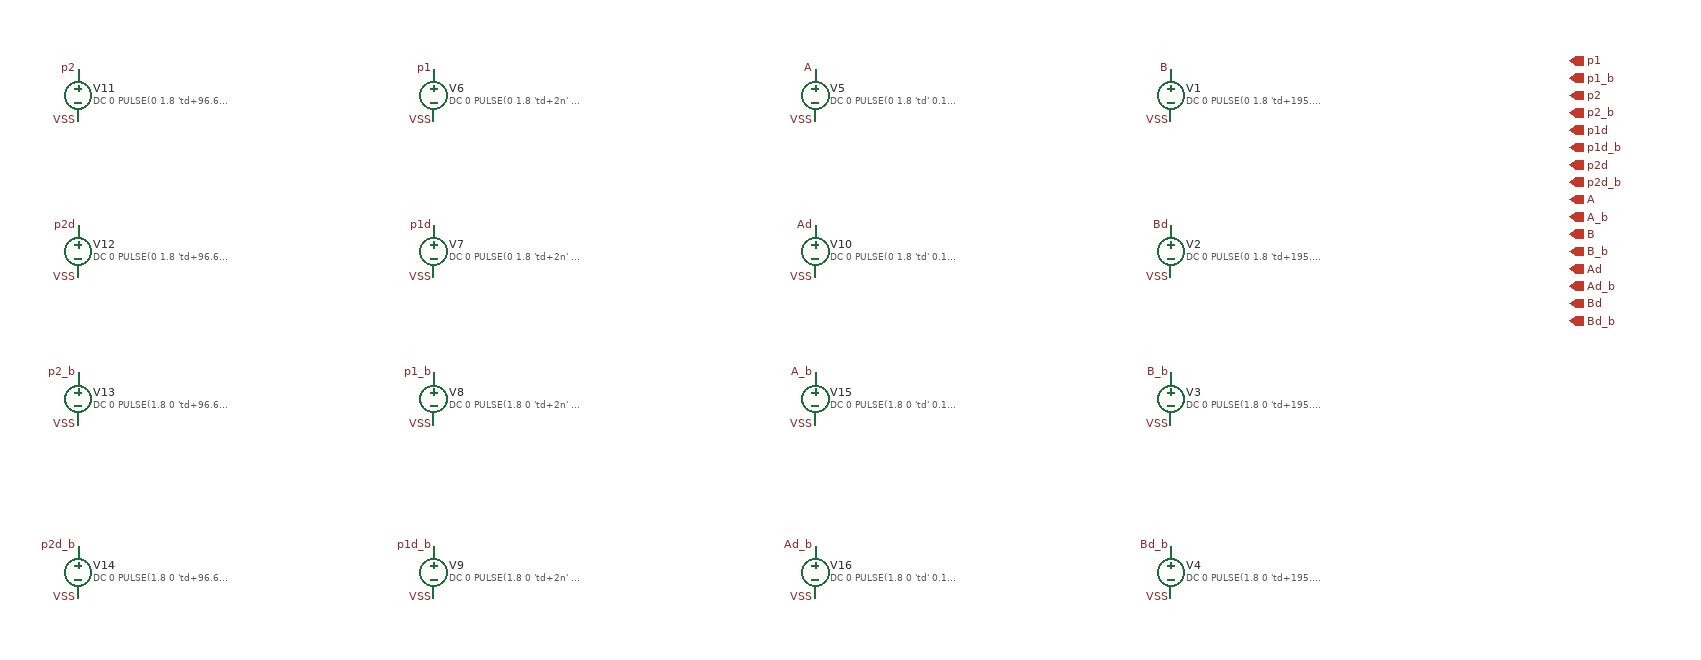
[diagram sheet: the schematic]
v {xschem version=3.0.0 file_version=1.2 }
G {}
K {}
V {}
S {}
E {}
C {devices/vsource.sym} 470 -650 0 0 {name=V6 value="DC 0 PULSE(0 1.8 'td+2n' 0.1n 0.1n 90.45625n 195.3125n)"}
C {devices/lab_pin.sym} 470 -680 3 1 {name=l25 sig_type=std_logic lab=p1}
C {devices/vsource.sym} 470 -470 0 0 {name=V7 value="DC 0 PULSE(0 1.8 'td+2n' 0.1n 0.1n 91.45625n 195.3125n)"}
C {devices/lab_pin.sym} 470 -500 3 1 {name=l27 sig_type=std_logic lab=p1d}
C {devices/vsource.sym} 470 -300 0 0 {name=V8 value="DC 0 PULSE(1.8 0 'td+2n' 0.1n 0.1n 90.45625n 195.3125n)"}
C {devices/lab_pin.sym} 470 -330 3 1 {name=l31 sig_type=std_logic lab=p1_b}
C {devices/vsource.sym} 470 -100 0 0 {name=V9 value="DC 0 PULSE(1.8 0 'td+2n' 0.1n 0.1n 91.45625n 195.3125n)"}
C {devices/lab_pin.sym} 470 -130 3 1 {name=l33 sig_type=std_logic lab=p1d_b}
C {devices/vsource.sym} 60 -650 0 0 {name=V11 value="DC 0 PULSE(0 1.8 'td+96.65625n' 0.1n 0.1n 90.45625n 195.3125n)"}
C {devices/lab_pin.sym} 60 -680 3 1 {name=l43 sig_type=std_logic lab=p2}
C {devices/vsource.sym} 60 -470 0 0 {name=V12 value="DC 0 PULSE(0 1.8 'td+96.65625n' 0.1n 0.1n 91.45625n 195.3125n)"}
C {devices/lab_pin.sym} 60 -500 3 1 {name=l45 sig_type=std_logic lab=p2d}
C {devices/vsource.sym} 60 -300 0 0 {name=V13 value="DC 0 PULSE(1.8 0 'td+96.65625n' 0.1n 0.1n 90.45625n 195.3125n)"}
C {devices/lab_pin.sym} 60 -330 3 1 {name=l47 sig_type=std_logic lab=p2_b}
C {devices/vsource.sym} 60 -100 0 0 {name=V14 value="DC 0 PULSE(1.8 0 'td+96.65625n' 0.1n 0.1n 91.45625n 195.3125n)"}
C {devices/lab_pin.sym} 60 -130 3 1 {name=l49 sig_type=std_logic lab=p2d_b}
C {devices/vsource.sym} 1320 -650 0 0 {name=V1 value="DC 0 PULSE(0 1.8 'td+195.3125n' 0.1n 0.1n 191.1125n 390.625n)"}
C {devices/lab_pin.sym} 1320 -680 3 1 {name=l2 sig_type=std_logic lab=B}
C {devices/vsource.sym} 1320 -470 0 0 {name=V2 value="DC 0 PULSE(0 1.8 'td+195.3125n' 0.1n 0.1n 193.1125n 390.625n)"}
C {devices/lab_pin.sym} 1320 -500 3 1 {name=l4 sig_type=std_logic lab=Bd}
C {devices/vsource.sym} 1320 -300 0 0 {name=V3 value="DC 0 PULSE(1.8 0 'td+195.3125n' 0.1n 0.1n 191.1125n 390.625n)"}
C {devices/lab_pin.sym} 1320 -330 3 1 {name=l6 sig_type=std_logic lab=B_b}
C {devices/vsource.sym} 1320 -100 0 0 {name=V4 value="DC 0 PULSE(1.8 0 'td+195.3125n' 0.1n 0.1n 193.1125n 390.625n)"}
C {devices/lab_pin.sym} 1320 -130 3 1 {name=l8 sig_type=std_logic lab=Bd_b}
C {devices/vsource.sym} 910 -650 0 0 {name=V5 value="DC 0 PULSE(0 1.8 'td' 0.1n 0.1n 191.1125n 390.625n)"}
C {devices/lab_pin.sym} 910 -680 3 1 {name=l10 sig_type=std_logic lab=A}
C {devices/vsource.sym} 910 -470 0 0 {name=V10 value="DC 0 PULSE(0 1.8 'td' 0.1n 0.1n 193.1125n 390.625n)"}
C {devices/lab_pin.sym} 910 -500 3 1 {name=l12 sig_type=std_logic lab=Ad}
C {devices/vsource.sym} 910 -300 0 0 {name=V15 value="DC 0 PULSE(1.8 0 'td' 0.1n 0.1n 191.1125n 390.625n)"}
C {devices/lab_pin.sym} 910 -330 3 1 {name=l14 sig_type=std_logic lab=A_b}
C {devices/vsource.sym} 910 -100 0 0 {name=V16 value="DC 0 PULSE(1.8 0 'td' 0.1n 0.1n 193.1125n 390.625n)"}
C {devices/lab_pin.sym} 910 -130 3 1 {name=l16 sig_type=std_logic lab=Ad_b}
C {devices/lab_pin.sym} 60 -620 3 0 {name=l1 sig_type=std_logic lab=VSS}
C {devices/lab_pin.sym} 60 -440 3 0 {name=l3 sig_type=std_logic lab=VSS}
C {devices/lab_pin.sym} 60 -270 3 0 {name=l5 sig_type=std_logic lab=VSS}
C {devices/lab_pin.sym} 60 -70 3 0 {name=l7 sig_type=std_logic lab=VSS}
C {devices/lab_pin.sym} 470 -620 3 0 {name=l9 sig_type=std_logic lab=VSS}
C {devices/lab_pin.sym} 470 -440 3 0 {name=l11 sig_type=std_logic lab=VSS}
C {devices/lab_pin.sym} 470 -270 3 0 {name=l13 sig_type=std_logic lab=VSS}
C {devices/lab_pin.sym} 470 -70 3 0 {name=l15 sig_type=std_logic lab=VSS}
C {devices/lab_pin.sym} 910 -620 3 0 {name=l17 sig_type=std_logic lab=VSS}
C {devices/lab_pin.sym} 910 -440 3 0 {name=l18 sig_type=std_logic lab=VSS}
C {devices/lab_pin.sym} 910 -270 3 0 {name=l19 sig_type=std_logic lab=VSS}
C {devices/lab_pin.sym} 910 -70 3 0 {name=l20 sig_type=std_logic lab=VSS}
C {devices/lab_pin.sym} 1320 -620 3 0 {name=l21 sig_type=std_logic lab=VSS}
C {devices/lab_pin.sym} 1320 -440 3 0 {name=l22 sig_type=std_logic lab=VSS}
C {devices/lab_pin.sym} 1320 -270 3 0 {name=l23 sig_type=std_logic lab=VSS}
C {devices/lab_pin.sym} 1320 -70 3 0 {name=l24 sig_type=std_logic lab=VSS}
C {devices/opin.sym} 1780 -690 0 0 {name=p1 lab=p1}
C {devices/opin.sym} 1780 -670 0 0 {name=p2 lab=p1_b}
C {devices/opin.sym} 1780 -650 0 0 {name=p3 lab=p2}
C {devices/opin.sym} 1780 -630 0 0 {name=p4 lab=p2_b}
C {devices/opin.sym} 1780 -610 0 0 {name=p5 lab=p1d}
C {devices/opin.sym} 1780 -590 0 0 {name=p6 lab=p1d_b}
C {devices/opin.sym} 1780 -570 0 0 {name=p7 lab=p2d}
C {devices/opin.sym} 1780 -550 0 0 {name=p8 lab=p2d_b}
C {devices/opin.sym} 1780 -530 0 0 {name=p9 lab=A}
C {devices/opin.sym} 1780 -510 0 0 {name=p10 lab=A_b}
C {devices/opin.sym} 1780 -490 0 0 {name=p11 lab=B}
C {devices/opin.sym} 1780 -470 0 0 {name=p12 lab=B_b}
C {devices/opin.sym} 1780 -450 0 0 {name=p13 lab=Ad}
C {devices/opin.sym} 1780 -430 0 0 {name=p14 lab=Ad_b}
C {devices/opin.sym} 1780 -410 0 0 {name=p15 lab=Bd}
C {devices/opin.sym} 1780 -390 0 0 {name=p16 lab=Bd_b}
